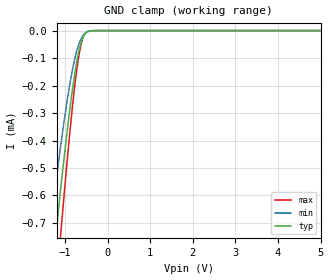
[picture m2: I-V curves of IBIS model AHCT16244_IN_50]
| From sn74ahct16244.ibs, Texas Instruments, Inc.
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[Model]   AHCT16244_IN_50
Model_type  Input
Vinl=0.8
Vinh=2.0
| variable   typ   min   max
C_comp   0.87pF   0.75pF   0.98pF
[Temperature Range]   40   100   -40
| Ambient temperature   25   85   -40
[Voltage range]   5   4.5   5.5
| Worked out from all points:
|   GND clamp passes 1 mA (typ) near -1.38 V on its own axis
[GND Clamp]
| AHCT16244_IN_50
|   Voltage   I(typ)   I(min)   I(max)
-5V       -7.834mA   -6.491mA   -8.926mA
-1.4V     -1.031mA   -788.3uA   -1.305mA
-1.345V   -943.5uA   -717uA     -1.198mA
-1.22V    -749.9uA   -559.7uA   -959.9uA
-1.195V   -712.2uA   -529.2uA   -913uA
-1.105V   -579.3uA   -422.4uA   -746.6uA
-1.08V    -543.4uA   -393.8uA   -701.3uA
-890mV    -289.7uA   -197.1uA   -375.4uA
-725mV    -114.1uA   -74.02uA   -143.2uA
-605mV    -34.41uA   -24.51uA   -38.71uA
-475mV    -4.506uA   -3.59uA    -3.661uA
5V        7.166nA    474.1pA    66.12nA
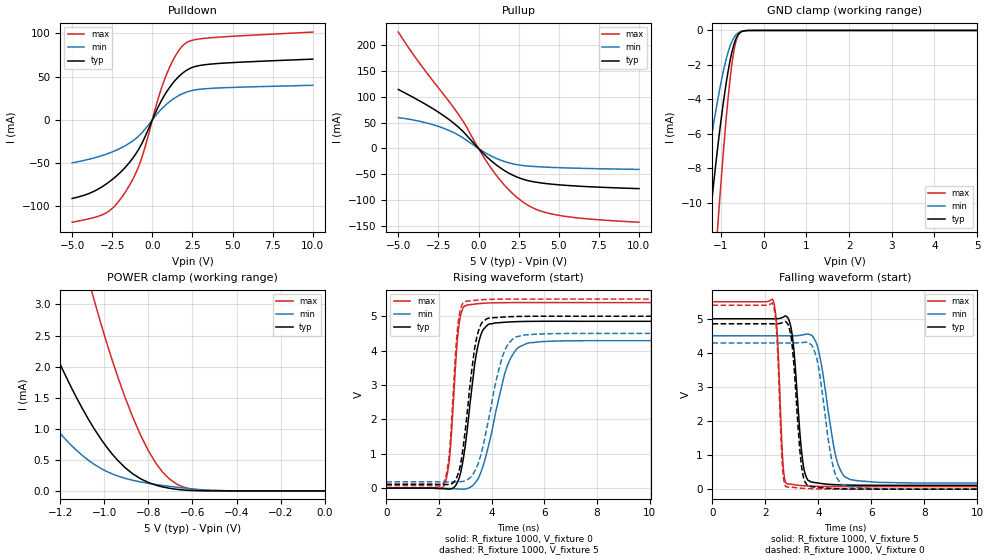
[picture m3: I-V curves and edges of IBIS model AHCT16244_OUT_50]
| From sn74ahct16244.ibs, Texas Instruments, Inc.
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[Model]   AHCT16244_OUT_50
Model_type  3-state
Enable   Active-Low
Vref =   0
Rref =   1000
Cref =   50p
Vmeas =   2.5
| variable   typ   min   max
C_comp   2.75pF   2.26pF   3.02pF
| C_pullup   3.99pF   2.46pF   5.30pF
| C_pulldown   3.20pF   2.63pF   3.95pF
| C_tri-state   2.75pF   2.26pF   3.02pF
[Temperature Range]   40   100   -40
| Ambient temperature   25   85   -40
[Voltage range]   5   4.5   5.5
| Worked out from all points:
|   slope of the pulldown table from 0 to 0.75 V, typ, clamps not added: 26.6 ohm
|   slope of the pullup table from 0 to 0.75 V, typ, clamps not added: 33.1 ohm
|   GND clamp passes 1 mA (typ) near -0.72 V on its own axis
|   POWER clamp passes 1 mA (typ) near -1.05 V on its own axis
|   rising waveform, R_fixture 1000, V_fixture 0: 20-80 % time 467ps typ, 784ps min, 275ps max; typ from 0 V to 4.85 V
|   falling waveform, R_fixture 1000, V_fixture 5: 20-80 % time 287ps typ, 516ps min, 175ps max; typ from 5 V to 0.112 V
|   rising waveform, R_fixture 1000, V_fixture 5: 20-80 % time 445ps typ, 723ps min, 268ps max; typ from 0.112 V to 5 V
|   falling waveform, R_fixture 1000, V_fixture 0: 20-80 % time 271ps typ, 468ps min, 168ps max; typ from 4.85 V to 0 V
[GND Clamp]
| AHCT16244_OUT_50
|   Voltage   I(typ)   I(min)   I(max)
-5V       -148.1mA   -97.16mA   -188.3mA
-1.56V    -18.9mA    -11.94mA   -29.92mA
-1.51V    -17.49mA   -11.02mA   -27.88mA
-1.28V    -11.44mA   -7.079mA   -18.8mA
-1.255V   -10.83mA   -6.679mA   -17.85mA
-1.08V    -6.843mA   -4.075mA   -11.5mA
-1.06V    -6.423mA   -3.803mA   -10.81mA
-885mV    -3.155mA   -1.729mA   -5.292mA
-775mV    -1.597mA   -824.7uA   -2.548mA
-675mV    -647.9uA   -336.5uA   -897.2uA
-555mV    -126.5uA   -84.36uA   -129uA
5V        48.57nA    6.899uA    454.2nA
[POWER Clamp]
| AHCT16244_OUT_50
|   Voltage   I(typ)   I(min)   I(max)
-5V       73.67mA    47.07mA    119.7mA
-1.595V   5.839mA    3.125mA    12.39mA
-1.34V    3.216mA    1.58mA     7.528mA
-1.19V    1.961mA    885.4uA    5.08mA
-1.07V    1.142mA    488.5uA    3.381mA
-1.045V   996.4uA    426.6uA    3.06mA
-940mV    495.6uA    241.5uA    1.848mA
-835mV    195.2uA    144.2uA    894.5uA
-765mV    92.31uA    103uA      441uA
-705mV    43.31uA    74.13uA    193.3uA
-580mV    3.512uA    25.92uA    17.11uA
-84.45fV  48.57nA    2.7nA      695.6nA
[Pulldown]
| AHCT16244_OUT_50
|   Voltage   I(typ)   I(min)   I(max)
-5V       -90.8mA    -49.6mA    -118.2mA
-3.845V   -84.23mA   -45.02mA   -113.8mA
-2.86V    -73.86mA   -39.54mA   -107.2mA
-2.28V    -65.49mA   -35.3mA    -98.04mA
-1.62V    -53.42mA   -29.07mA   -81.48mA
-710mV    -29.2mA    -16.09mA   -46.63mA
335mV     13.86mA    7.723mA    22.89mA
860mV     31.52mA    17.66mA    51.37mA
1.455V    46.28mA    25.98mA    74.4mA
2.025V    55.84mA    31.31mA    87.84mA
3.59V     64.27mA    36.27mA    94.68mA
10V       70.09mA    39.86mA    101.3mA
[Pullup]
| AHCT16244_OUT_50
|   Voltage   I(typ)   I(min)   I(max)
-5V       114.1mA    59.75mA    225.1mA
-3.725V   92.89mA    52.95mA    166.9mA
-1.735V   53.49mA    33.35mA    86.58mA
-925mV    31.51mA    19.63mA    50.82mA
130mV     -4.289mA   -2.68mA    -6.791mA
895mV     -26.47mA   -16.08mA   -42.9mA
1.71V     -44.45mA   -26.08mA   -74.12mA
2.525V    -56.78mA   -31.93mA   -97.85mA
3.535V    -64.91mA   -34.96mA   -116.9mA
4.77V     -69.59mA   -36.84mA   -128mA
6.785V    -73.77mA   -38.66mA   -136.1mA
10V       -77.6mA    -40.43mA   -142.5mA
[Ramp]
| AHCT16244_OUT_50
| variable   typ   min   max
dV/dt_r   2.93/4.92E-10   2.59/8.26E-10   3.25/2.87E-10
dV/dt_f   2.98/3.00E-10   2.62/5.46E-10   3.30/1.83E-10
R_load = 1000
[Rising Waveform]
| AHCT16244_OUT_50
R_fixture =   1000
C_fixture =   0
L_fixture =   0
V_fixture =   0
V_fixture_min = 0
V_fixture_max = 0
|   Time   V(typ)   V(min)   V(max)
0s        230.9pV    442pV      108.2pV
2.205ns   -17.83mV   -5.255mV   109.1mV
2.405ns   -27.78mV   -11.53mV   900.7mV
2.755ns   270.4mV    -26.41mV   4.718V
3.09ns    1.818V     -8.913mV   5.332V
3.385ns   3.749V     162.4mV    5.357V
3.675ns   4.606V     645.6mV    5.378V
4.615ns   4.831V     3.593V     5.396V
5.475ns   4.852V     4.233V     5.398V
50ns      4.853V     4.289V     5.397V
[Falling Waveform]
| AHCT16244_OUT_50
R_fixture =   1000
C_fixture =   0
L_fixture =   0
V_fixture =   5
V_fixture_min = 4.5
V_fixture_max = 5.5
|   Time   V(typ)   V(min)   V(max)
0s        5V         4.5V       5.5V
2.29ns    4.999V     4.5V       5.534V
2.445ns   5.001V     4.5V       4.591V
2.67ns    5.047V     4.5V       682.9mV
2.84ns    5.036V     4.499V     147.7mV
3.46ns    580.3mV    4.535V     98.09mV
4.105ns   165.7mV    3.697V     80.52mV
4.73ns    127.3mV    763.5mV    75.94mV
5.52ns    114.3mV    242.8mV    74.25mV
50ns      112.4mV    181.3mV    74.33mV
[Rising Waveform]
| AHCT16244_OUT_50
R_fixture =   1000
C_fixture =   0
L_fixture =   0
V_fixture =   5
V_fixture_min = 4.5
V_fixture_max = 5.5
|   Time   V(typ)   V(min)   V(max)
0s        112.4mV    181.3mV    74.33mV
2.19ns    103.2mV    177.9mV    178.3mV
2.39ns    104.8mV    176.5mV    976.9mV
2.735ns   437mV      182.1mV    4.845V
3.065ns   2.144V     238.7mV    5.444V
3.35ns    4.044V     480.6mV    5.463V
3.62ns    4.8V       1.057V     5.481V
4.435ns   4.976V     3.881V     5.498V
5.23ns    4.998V     4.454V     5.501V
50ns      5V         4.5V       5.5V
[Falling Waveform]
| AHCT16244_OUT_50
R_fixture =   1000
C_fixture =   0
L_fixture =   0
V_fixture =   0
V_fixture_min = 0
V_fixture_max = 0
|   Time   V(typ)   V(min)   V(max)
0s        4.853V     4.289V     5.397V
2.28ns    4.852V     4.289V     5.43V
2.44ns    4.853V     4.289V     4.387V
2.655ns   4.888V     4.289V     556.7mV
2.845ns   4.844V     4.288V     57.93mV
3.38ns    599.3mV    4.301V     25.94mV
3.755ns   70.07mV    4.218V     12.09mV
4.575ns   16.77mV    611.6mV    2.22mV
5.165ns   4.678mV    70.04mV    406.3uV
50ns      -8.869nV   39.94nV    14.46nV
